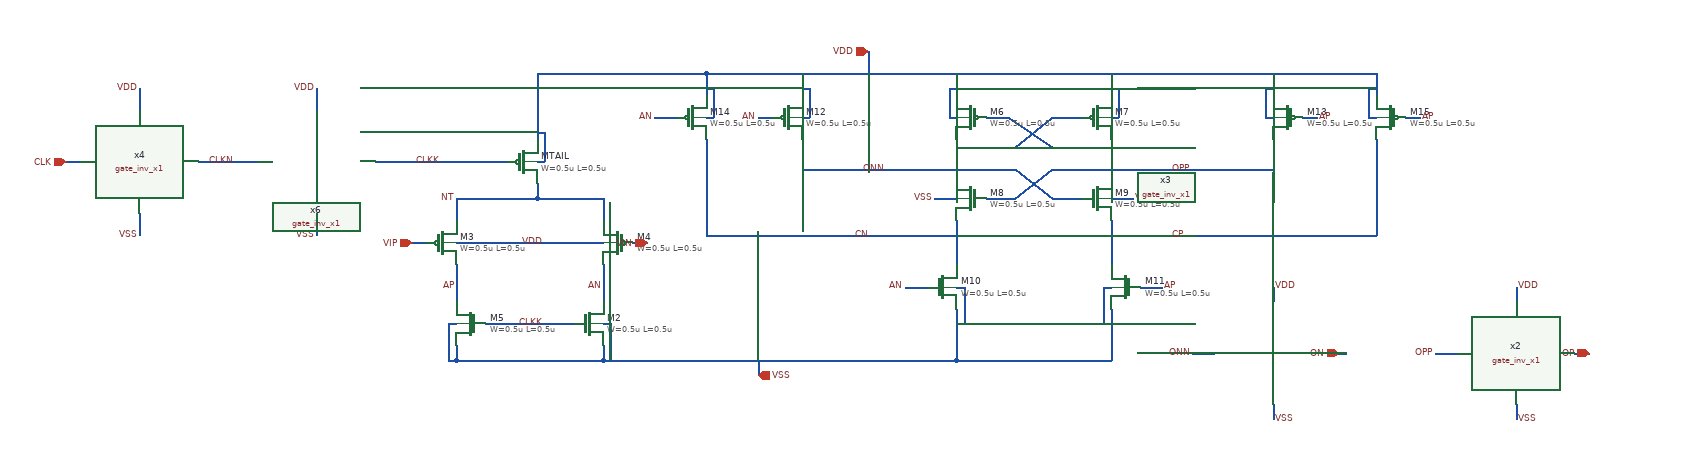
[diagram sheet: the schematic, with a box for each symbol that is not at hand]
v {xschem version=3.4.8RC file_version=1.3}
G {}
K {}
V {}
S {}
F {}
E {}
N 1350 -480 1350 -420 {lab=CN}
N 1560 -480 1560 -420 {lab=CP}
N 1350 -360 1350 -290 {lab=VSS}
N 1350 -290 1560 -290 {lab=VSS}
N 1560 -360 1560 -290 {lab=VSS}
N 1350 -590 1350 -540 {lab=ONN}
N 1560 -590 1560 -540 {lab=OPP}
N 1010 -680 1010 -650 {lab=VDD}
N 1010 -680 1920 -680 {lab=VDD}
N 1920 -680 1920 -650 {lab=VDD}
N 1780 -680 1780 -650 {lab=VDD}
N 1560 -680 1560 -650 {lab=VDD}
N 1350 -680 1350 -650 {lab=VDD}
N 1140 -680 1140 -650 {lab=VDD}
N 1140 -590 1140 -570 {lab=ONN}
N 1140 -570 1140 -560 {lab=ONN}
N 1560 -550 1780 -550 {lab=OPP}
N 1780 -590 1780 -550 {lab=OPP}
N 1920 -590 1920 -460 {lab=CP}
N 1560 -460 1920 -460 {lab=CP}
N 780 -680 780 -590 {lab=VDD}
N 780 -680 1010 -680 {lab=VDD}
N 780 -530 780 -510 {lab=#net1}
N 780 -510 870 -510 {lab=#net1}
N 870 -510 870 -480 {lab=#net1}
N 670 -510 780 -510 {lab=#net1}
N 670 -510 670 -480 {lab=#net1}
N 670 -420 670 -370 {lab=AP}
N 870 -420 870 -370 {lab=AN}
N 870 -290 1350 -290 {lab=VSS}
N 870 -310 870 -290 {lab=VSS}
N 670 -310 670 -290 {lab=VSS}
N 670 -290 870 -290 {lab=VSS}
N 1080 -290 1080 -270 {lab=VSS}
N 710 -340 830 -340 {lab=CLKK}
N 610 -450 630 -450 {lab=VIP}
N 910 -450 930 -450 {lab=VIN}
N 670 -450 870 -450 {lab=VDD}
N 1230 -710 1230 -680 {lab=VDD}
N 940 -620 970 -620 {lab=AN}
N 1080 -620 1100 -620 {lab=AN}
N 1820 -620 1840 -620 {lab=AP}
N 1960 -620 1980 -620 {lab=AP}
N 1280 -390 1310 -390 {lab=AN}
N 1600 -390 1630 -390 {lab=AP}
N 720 -560 740 -560 {lab=CLKK}
N 650 -560 720 -560 {lab=CLKK}
N 140 -560 160 -560 {lab=CLK}
N 320 -560 400 -560 {lab=CLKN}
N 240 -490 240 -460 {lab=VSS}
N 480 -490 480 -460 {lab=VSS}
N 240 -660 240 -630 {lab=VDD}
N 480 -660 480 -630 {lab=VDD}
N 560 -560 650 -560 {lab=CLKK}
N 1010 -620 1020 -620 {lab=VDD}
N 1020 -660 1020 -620 {lab=VDD}
N 1010 -660 1020 -660 {lab=VDD}
N 1140 -620 1150 -620 {lab=VDD}
N 1150 -660 1150 -620 {lab=VDD}
N 1140 -660 1150 -660 {lab=VDD}
N 1340 -620 1350 -620 {lab=VDD}
N 1340 -660 1340 -620 {lab=VDD}
N 1340 -660 1350 -660 {lab=VDD}
N 1560 -620 1570 -620 {lab=VDD}
N 1570 -660 1570 -620 {lab=VDD}
N 1560 -660 1570 -660 {lab=VDD}
N 1770 -620 1780 -620 {lab=VDD}
N 1770 -660 1770 -620 {lab=VDD}
N 1770 -660 1780 -660 {lab=VDD}
N 1910 -620 1920 -620 {lab=VDD}
N 1910 -660 1910 -620 {lab=VDD}
N 1910 -660 1920 -660 {lab=VDD}
N 660 -340 670 -340 {lab=VSS}
N 660 -340 660 -290 {lab=VSS}
N 660 -290 670 -290 {lab=VSS}
N 870 -340 880 -340 {lab=VSS}
N 880 -340 880 -290 {lab=VSS}
N 1320 -510 1350 -510 {lab=VSS}
N 1560 -510 1590 -510 {lab=VSS}
N 1780 -230 1780 -210 {lab=VSS}
N 1780 -390 1780 -370 {lab=VDD}
N 1860 -300 1880 -300 {lab=ON}
N 1010 -590 1010 -460 {lab=CN}
N 1010 -460 1350 -460 {lab=CN}
N 1390 -510 1430 -510 {lab=OPP}
N 1430 -510 1480 -550 {lab=OPP}
N 1480 -550 1560 -550 {lab=OPP}
N 1480 -510 1520 -510 {lab=ONN}
N 1430 -550 1480 -510 {lab=ONN}
N 1350 -550 1430 -550 {lab=ONN}
N 1140 -550 1350 -550 {lab=ONN}
N 1140 -560 1140 -550 {lab=ONN}
N 1480 -620 1520 -620 {lab=ONN}
N 1390 -620 1420 -620 {lab=OPP}
N 1670 -300 1700 -300 {lab=ONN}
N 2110 -230 2110 -210 {lab=VSS}
N 2110 -390 2110 -370 {lab=VDD}
N 2190 -300 2210 -300 {lab=OP}
N 2000 -300 2030 -300 {lab=OPP}
N 1350 -390 1360 -390 {lab=VSS}
N 1360 -390 1360 -340 {lab=VSS}
N 1350 -340 1360 -340 {lab=VSS}
N 1550 -390 1560 -390 {lab=VSS}
N 1550 -390 1550 -340 {lab=VSS}
N 1550 -340 1560 -340 {lab=VSS}
N 780 -560 790 -560 {lab=VDD}
N 790 -600 790 -560 {lab=VDD}
N 780 -600 790 -600 {lab=VDD}
N 1350 -580 1430 -580 {lab=ONN}
N 1430 -580 1480 -620 {lab=ONN}
N 1480 -580 1560 -580 {lab=OPP}
N 1420 -620 1480 -580 {lab=OPP}
C {symbols/pfet_03v3.sym} 760 -560 0 0 {name=MTAIL
L=0.5u
W=0.5u
nf=1
m=6
ad="'int((nf+1)/2) * W/nf * 0.18u'"
pd="'2*int((nf+1)/2) * (W/nf + 0.18u)'"
as="'int((nf+2)/2) * W/nf * 0.18u'"
ps="'2*int((nf+2)/2) * (W/nf + 0.18u)'"
nrd="'0.18u / W'" nrs="'0.18u / W'"
sa=0 sb=0 sd=0
model=pfet_03v3
spiceprefix=X
}
C {symbols/nfet_03v3.sym} 850 -340 0 0 {name=M2
L=0.5u
W=0.5u
nf=1
m=2
ad="'int((nf+1)/2) * W/nf * 0.18u'"
pd="'2*int((nf+1)/2) * (W/nf + 0.18u)'"
as="'int((nf+2)/2) * W/nf * 0.18u'"
ps="'2*int((nf+2)/2) * (W/nf + 0.18u)'"
nrd="'0.18u / W'" nrs="'0.18u / W'"
sa=0 sb=0 sd=0
model=nfet_03v3
spiceprefix=X
}
C {iopin.sym} 1080 -270 0 1 {name=p1 lab=VSS}
C {symbols/pfet_03v3.sym} 650 -450 0 0 {name=M3
L=0.5u
W=0.5u
nf=1
m=4
ad="'int((nf+1)/2) * W/nf * 0.18u'"
pd="'2*int((nf+1)/2) * (W/nf + 0.18u)'"
as="'int((nf+2)/2) * W/nf * 0.18u'"
ps="'2*int((nf+2)/2) * (W/nf + 0.18u)'"
nrd="'0.18u / W'" nrs="'0.18u / W'"
sa=0 sb=0 sd=0
model=pfet_03v3
spiceprefix=X
}
C {symbols/pfet_03v3.sym} 890 -450 0 1 {name=M4
L=0.5u
W=0.5u
nf=1
m=4
ad="'int((nf+1)/2) * W/nf * 0.18u'"
pd="'2*int((nf+1)/2) * (W/nf + 0.18u)'"
as="'int((nf+2)/2) * W/nf * 0.18u'"
ps="'2*int((nf+2)/2) * (W/nf + 0.18u)'"
nrd="'0.18u / W'" nrs="'0.18u / W'"
sa=0 sb=0 sd=0
model=pfet_03v3
spiceprefix=X
}
C {symbols/nfet_03v3.sym} 690 -340 0 1 {name=M5
L=0.5u
W=0.5u
nf=1
m=2
ad="'int((nf+1)/2) * W/nf * 0.18u'"
pd="'2*int((nf+1)/2) * (W/nf + 0.18u)'"
as="'int((nf+2)/2) * W/nf * 0.18u'"
ps="'2*int((nf+2)/2) * (W/nf + 0.18u)'"
nrd="'0.18u / W'" nrs="'0.18u / W'"
sa=0 sb=0 sd=0
model=nfet_03v3
spiceprefix=X
}
C {symbols/pfet_03v3.sym} 1370 -620 0 1 {name=M6
L=0.5u
W=0.5u
nf=1
m=2
ad="'int((nf+1)/2) * W/nf * 0.18u'"
pd="'2*int((nf+1)/2) * (W/nf + 0.18u)'"
as="'int((nf+2)/2) * W/nf * 0.18u'"
ps="'2*int((nf+2)/2) * (W/nf + 0.18u)'"
nrd="'0.18u / W'" nrs="'0.18u / W'"
sa=0 sb=0 sd=0
model=pfet_03v3
spiceprefix=X
}
C {symbols/pfet_03v3.sym} 1540 -620 0 0 {name=M7
L=0.5u
W=0.5u
nf=1
m=2
ad="'int((nf+1)/2) * W/nf * 0.18u'"
pd="'2*int((nf+1)/2) * (W/nf + 0.18u)'"
as="'int((nf+2)/2) * W/nf * 0.18u'"
ps="'2*int((nf+2)/2) * (W/nf + 0.18u)'"
nrd="'0.18u / W'" nrs="'0.18u / W'"
sa=0 sb=0 sd=0
model=pfet_03v3
spiceprefix=X
}
C {symbols/nfet_03v3.sym} 1370 -510 0 1 {name=M8
L=0.5u
W=0.5u
nf=1
m=2
ad="'int((nf+1)/2) * W/nf * 0.18u'"
pd="'2*int((nf+1)/2) * (W/nf + 0.18u)'"
as="'int((nf+2)/2) * W/nf * 0.18u'"
ps="'2*int((nf+2)/2) * (W/nf + 0.18u)'"
nrd="'0.18u / W'" nrs="'0.18u / W'"
sa=0 sb=0 sd=0
model=nfet_03v3
spiceprefix=X
}
C {symbols/nfet_03v3.sym} 1540 -510 0 0 {name=M9
L=0.5u
W=0.5u
nf=1
m=2
ad="'int((nf+1)/2) * W/nf * 0.18u'"
pd="'2*int((nf+1)/2) * (W/nf + 0.18u)'"
as="'int((nf+2)/2) * W/nf * 0.18u'"
ps="'2*int((nf+2)/2) * (W/nf + 0.18u)'"
nrd="'0.18u / W'" nrs="'0.18u / W'"
sa=0 sb=0 sd=0
model=nfet_03v3
spiceprefix=X
}
C {symbols/nfet_03v3.sym} 1330 -390 0 0 {name=M10
L=0.5u
W=0.5u
nf=1
m=4
ad="'int((nf+1)/2) * W/nf * 0.18u'"
pd="'2*int((nf+1)/2) * (W/nf + 0.18u)'"
as="'int((nf+2)/2) * W/nf * 0.18u'"
ps="'2*int((nf+2)/2) * (W/nf + 0.18u)'"
nrd="'0.18u / W'" nrs="'0.18u / W'"
sa=0 sb=0 sd=0
model=nfet_03v3
spiceprefix=X
}
C {symbols/nfet_03v3.sym} 1580 -390 0 1 {name=M11
L=0.5u
W=0.5u
nf=1
m=4
ad="'int((nf+1)/2) * W/nf * 0.18u'"
pd="'2*int((nf+1)/2) * (W/nf + 0.18u)'"
as="'int((nf+2)/2) * W/nf * 0.18u'"
ps="'2*int((nf+2)/2) * (W/nf + 0.18u)'"
nrd="'0.18u / W'" nrs="'0.18u / W'"
sa=0 sb=0 sd=0
model=nfet_03v3
spiceprefix=X
}
C {symbols/pfet_03v3.sym} 1120 -620 0 0 {name=M12
L=0.5u
W=0.5u
nf=1
m=2
ad="'int((nf+1)/2) * W/nf * 0.18u'"
pd="'2*int((nf+1)/2) * (W/nf + 0.18u)'"
as="'int((nf+2)/2) * W/nf * 0.18u'"
ps="'2*int((nf+2)/2) * (W/nf + 0.18u)'"
nrd="'0.18u / W'" nrs="'0.18u / W'"
sa=0 sb=0 sd=0
model=pfet_03v3
spiceprefix=X
}
C {symbols/pfet_03v3.sym} 1800 -620 0 1 {name=M13
L=0.5u
W=0.5u
nf=1
m=2
ad="'int((nf+1)/2) * W/nf * 0.18u'"
pd="'2*int((nf+1)/2) * (W/nf + 0.18u)'"
as="'int((nf+2)/2) * W/nf * 0.18u'"
ps="'2*int((nf+2)/2) * (W/nf + 0.18u)'"
nrd="'0.18u / W'" nrs="'0.18u / W'"
sa=0 sb=0 sd=0
model=pfet_03v3
spiceprefix=X
}
C {symbols/pfet_03v3.sym} 990 -620 0 0 {name=M14
L=0.5u
W=0.5u
nf=1
m=2
ad="'int((nf+1)/2) * W/nf * 0.18u'"
pd="'2*int((nf+1)/2) * (W/nf + 0.18u)'"
as="'int((nf+2)/2) * W/nf * 0.18u'"
ps="'2*int((nf+2)/2) * (W/nf + 0.18u)'"
nrd="'0.18u / W'" nrs="'0.18u / W'"
sa=0 sb=0 sd=0
model=pfet_03v3
spiceprefix=X
}
C {symbols/pfet_03v3.sym} 1940 -620 0 1 {name=M15
L=0.5u
W=0.5u
nf=1
m=2
ad="'int((nf+1)/2) * W/nf * 0.18u'"
pd="'2*int((nf+1)/2) * (W/nf + 0.18u)'"
as="'int((nf+2)/2) * W/nf * 0.18u'"
ps="'2*int((nf+2)/2) * (W/nf + 0.18u)'"
nrd="'0.18u / W'" nrs="'0.18u / W'"
sa=0 sb=0 sd=0
model=pfet_03v3
spiceprefix=X
}
C {iopin.sym} 1230 -710 0 0 {name=p3 lab=VDD}
C {iopin.sym} 930 -450 0 0 {name=p4 lab=VIN}
C {iopin.sym} 610 -450 2 0 {name=p5 lab=VIP}
C {lab_pin.sym} 1320 -510 0 0 {name=p6 sig_type=std_logic lab=VSS
}
C {lab_pin.sym} 1590 -510 2 0 {name=p7 sig_type=std_logic lab=VSS
}
C {lab_pin.sym} 790 -450 1 0 {name=p8 sig_type=std_logic lab=VDD
}
C {lab_pin.sym} 870 -390 0 0 {name=p13 sig_type=std_logic lab=AN
}
C {lab_pin.sym} 670 -390 0 0 {name=p14 sig_type=std_logic lab=AP
}
C {lab_pin.sym} 940 -620 0 0 {name=p9 sig_type=std_logic lab=AN
}
C {lab_pin.sym} 1080 -620 0 0 {name=p10 sig_type=std_logic lab=AN
}
C {lab_pin.sym} 1280 -390 0 0 {name=p11 sig_type=std_logic lab=AN
}
C {lab_pin.sym} 1840 -620 2 0 {name=p12 sig_type=std_logic lab=AP
}
C {lab_pin.sym} 1980 -620 2 0 {name=p15 sig_type=std_logic lab=AP
}
C {lab_pin.sym} 1630 -390 2 0 {name=p16 sig_type=std_logic lab=AP
}
C {iopin.sym} 2210 -300 0 0 {name=p19 lab=OP}
C {iopin.sym} 140 -560 2 0 {name=p2 lab=CLK}
C {lab_pin.sym} 790 -340 1 0 {name=p17 sig_type=std_logic lab=CLKK
}
C {lab_pin.sym} 1780 -390 0 1 {name=p18 sig_type=std_logic lab=VDD
}
C {lab_pin.sym} 1780 -210 0 1 {name=p22 sig_type=std_logic lab=VSS
}
C {iopin.sym} 1870 -300 0 0 {name=p20 lab=ON}
C {lab_pin.sym} 650 -560 1 0 {name=p24 sig_type=std_logic lab=CLKK
}
C {lab_pin.sym} 240 -660 0 0 {name=p25 sig_type=std_logic lab=VDD
}
C {lab_pin.sym} 480 -460 0 0 {name=p26 sig_type=std_logic lab=VSS
}
C {designs/sar_adc/digital/gate_inv_x1/xschem/gate_inv_x1.sym} 260 -540 0 0 {name=x4}
C {designs/sar_adc/digital/gate_inv_x1/xschem/gate_inv_x1.sym} 500 -540 0 0 {name=x6}
C {lab_pin.sym} 240 -460 0 0 {name=p28 sig_type=std_logic lab=VSS
}
C {lab_pin.sym} 480 -660 0 0 {name=p29 sig_type=std_logic lab=VDD
}
C {lab_pin.sym} 370 -560 1 0 {name=p30 sig_type=std_logic lab=CLKN
}
C {designs/sar_adc/digital/gate_inv_x1/xschem/gate_inv_x1.sym} 1800 -280 0 0 {name=x3}
C {lab_pin.sym} 1220 -550 2 0 {name=p27 sig_type=std_logic lab=ONN
}
C {lab_pin.sym} 1670 -300 2 1 {name=p31 sig_type=std_logic lab=ONN
}
C {lab_pin.sym} 2110 -390 0 1 {name=p32 sig_type=std_logic lab=VDD
}
C {lab_pin.sym} 2110 -210 0 1 {name=p33 sig_type=std_logic lab=VSS
}
C {designs/sar_adc/digital/gate_inv_x1/xschem/gate_inv_x1.sym} 2130 -280 0 0 {name=x2}
C {lab_pin.sym} 2000 -300 2 1 {name=p35 sig_type=std_logic lab=OPP
}
C {lab_pin.sym} 1640 -550 2 0 {name=p34 sig_type=std_logic lab=OPP
}
C {lab_pin.sym} 1210 -460 2 0 {name=p21 sig_type=std_logic lab=CN
}
C {lab_pin.sym} 1640 -460 2 0 {name=p23 sig_type=std_logic lab=CP
}
C {lab_pin.sym} 670 -510 0 0 {name=p36 sig_type=std_logic lab=NT
}
